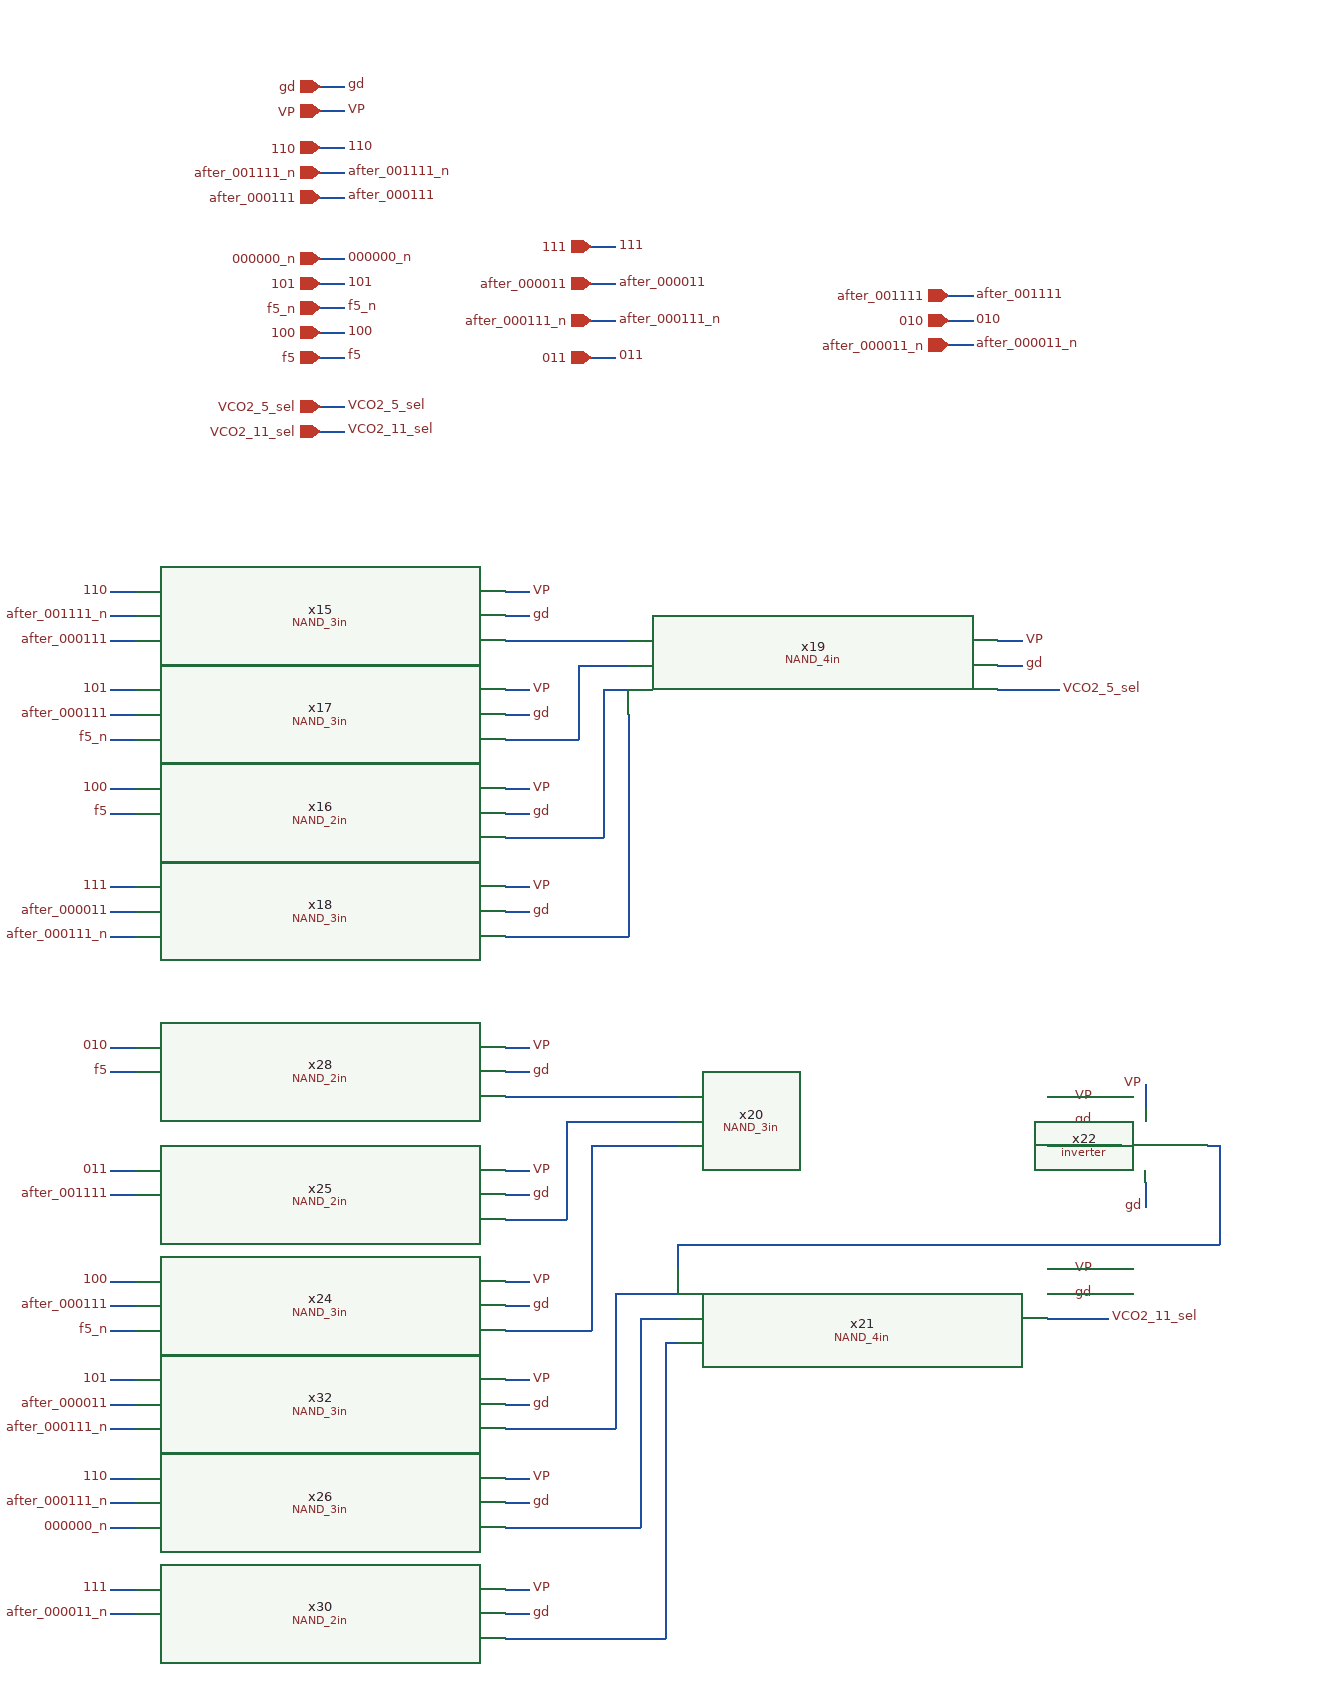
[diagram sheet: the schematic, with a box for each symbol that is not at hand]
v {xschem version=3.4.8RC file_version=1.3}
G {}
K {}
V {}
S {}
F {}
E {}
N 2000 -3300 2020 -3300 {lab=gd}
N 2000 -3280 2020 -3280 {lab=VP}
N 2000 -3230 2020 -3230 {lab=after_001111_n}
N 2000 -3210 2020 -3210 {lab=after_000111}
N 2000 -3160 2020 -3160 {lab=000000_n}
N 2000 -3250 2020 -3250 {lab=110}
N 2000 -3020 2020 -3020 {lab=VCO2_11_sel}
N 2000 -3040 2020 -3040 {lab=VCO2_5_sel}
N 2000 -3140 2020 -3140 {lab=101}
N 2000 -3120 2020 -3120 {lab=f5_n}
N 2000 -3100 2020 -3100 {lab=100}
N 2000 -3080 2020 -3080 {lab=f5}
N 2220 -3080 2240 -3080 {lab=011}
N 2220 -3110 2240 -3110 {lab=after_000111_n}
N 2220 -3140 2240 -3140 {lab=after_000011}
N 2220 -3170 2240 -3170 {lab=111}
N 2510 -3090 2530 -3090 {lab=after_000011_n}
N 2510 -3110 2530 -3110 {lab=010}
N 2510 -3130 2530 -3130 {lab=after_001111}
N 2150 -2870 2170 -2870 {lab=gd}
N 2150 -2890 2170 -2890 {lab=VP}
N 2150 -2710 2170 -2710 {lab=gd}
N 2150 -2730 2170 -2730 {lab=VP}
N 2150 -2790 2170 -2790 {lab=gd}
N 2150 -2810 2170 -2810 {lab=VP}
N 2150 -2630 2170 -2630 {lab=gd}
N 2150 -2650 2170 -2650 {lab=VP}
N 1830 -2890 1850 -2890 {lab=110}
N 1830 -2870 1850 -2870 {lab=after_001111_n}
N 1830 -2850 1850 -2850 {lab=after_000111}
N 1830 -2810 1850 -2810 {lab=101}
N 1830 -2790 1850 -2790 {lab=after_000111}
N 1830 -2770 1850 -2770 {lab=f5_n}
N 1830 -2650 1850 -2650 {lab=111}
N 1830 -2610 1850 -2610 {lab=after_000111_n}
N 1830 -2730 1850 -2730 {lab=100}
N 1830 -2710 1850 -2710 {lab=f5}
N 2150 -2850 2250 -2850 {lab=#net1}
N 2150 -2770 2210 -2770 {lab=#net2}
N 2210 -2830 2210 -2770 {lab=#net2}
N 2210 -2830 2250 -2830 {lab=#net2}
N 2230 -2810 2250 -2810 {lab=#net3}
N 2230 -2810 2230 -2690 {lab=#net3}
N 2150 -2690 2230 -2690 {lab=#net3}
N 2150 -2610 2250 -2610 {lab=#net4}
N 2250 -2790 2250 -2610 {lab=#net4}
N 2550 -2830 2570 -2830 {lab=gd}
N 2550 -2850 2570 -2850 {lab=VP}
N 2550 -2810 2600 -2810 {lab=VCO2_5_sel}
N 2590 -2460 2610 -2460 {lab=gd}
N 2590 -2480 2610 -2480 {lab=VP}
N 2150 -2310 2170 -2310 {lab=gd}
N 2150 -2330 2170 -2330 {lab=VP}
N 2150 -2400 2170 -2400 {lab=gd}
N 2150 -2420 2170 -2420 {lab=VP}
N 2150 -2290 2220 -2290 {lab=#net5}
N 2150 -2380 2200 -2380 {lab=#net6}
N 2150 -2500 2170 -2500 {lab=gd}
N 2150 -2520 2170 -2520 {lab=VP}
N 2150 -2060 2170 -2060 {lab=gd}
N 2150 -2080 2170 -2080 {lab=VP}
N 2150 -2040 2280 -2040 {lab=#net7}
N 2150 -2230 2170 -2230 {lab=gd}
N 2150 -2250 2170 -2250 {lab=VP}
N 2150 -2210 2240 -2210 {lab=#net8}
N 1830 -2630 1850 -2630 {lab=after_000011}
N 1830 -2330 1850 -2330 {lab=100}
N 1830 -2290 1850 -2290 {lab=f5_n}
N 1830 -2310 1850 -2310 {lab=after_000111}
N 1830 -2250 1850 -2250 {lab=101}
N 1830 -2210 1850 -2210 {lab=after_000111_n}
N 1830 -2230 1850 -2230 {lab=after_000011}
N 1830 -2520 1850 -2520 {lab=010}
N 1830 -2500 1850 -2500 {lab=f5}
N 1830 -2420 1850 -2420 {lab=011}
N 1830 -2400 1850 -2400 {lab=after_001111}
N 1830 -2080 1850 -2080 {lab=111}
N 1830 -2060 1850 -2060 {lab=after_000011_n}
N 2590 -2440 2650 -2440 {lab=#net9}
N 2150 -2150 2170 -2150 {lab=gd}
N 2150 -2170 2170 -2170 {lab=VP}
N 1830 -2170 1850 -2170 {lab=110}
N 1830 -2150 1850 -2150 {lab=after_000111_n}
N 1830 -2130 1850 -2130 {lab=000000_n}
N 2590 -2320 2610 -2320 {lab=gd}
N 2590 -2340 2610 -2340 {lab=VP}
N 2590 -2300 2640 -2300 {lab=VCO2_11_sel}
N 2670 -2410 2670 -2390 {lab=gd}
N 2670 -2490 2670 -2470 {lab=VP}
N 2720 -2440 2730 -2440 {lab=#net10}
N 2730 -2440 2730 -2360 {lab=#net10}
N 2290 -2360 2730 -2360 {lab=#net10}
N 2290 -2360 2290 -2340 {lab=#net10}
N 2150 -2480 2290 -2480 {lab=#net11}
N 2200 -2460 2200 -2380 {lab=#net6}
N 2200 -2460 2290 -2460 {lab=#net6}
N 2220 -2440 2290 -2440 {lab=#net5}
N 2220 -2440 2220 -2290 {lab=#net5}
N 2240 -2320 2240 -2210 {lab=#net8}
N 2240 -2320 2290 -2320 {lab=#net8}
N 2260 -2300 2290 -2300 {lab=#net12}
N 2260 -2300 2260 -2130 {lab=#net12}
N 2150 -2130 2260 -2130 {lab=#net12}
N 2280 -2280 2280 -2040 {lab=#net7}
N 2280 -2280 2290 -2280 {lab=#net7}
C {iopin.sym} 2000 -3300 2 0 {name=p46 lab=gd}
C {lab_wire.sym} 2020 -3300 2 0 {name=p53 sig_type=std_logic lab=gd}
C {iopin.sym} 2000 -3280 2 0 {name=p54 lab=VP}
C {ipin.sym} 2000 -3230 0 0 {name=p2 lab=after_001111_n}
C {lab_wire.sym} 2020 -3230 2 0 {name=p56 sig_type=std_logic lab=after_001111_n}
C {ipin.sym} 2000 -3210 0 0 {name=p57 lab=after_000111}
C {lab_wire.sym} 2020 -3210 2 0 {name=p58 sig_type=std_logic lab=after_000111}
C {ipin.sym} 2000 -3160 0 0 {name=p61 lab=000000_n}
C {lab_wire.sym} 2020 -3160 2 0 {name=p63 sig_type=std_logic lab=000000_n}
C {ipin.sym} 2000 -3250 0 0 {name=p20 lab=110}
C {lab_wire.sym} 2020 -3250 2 0 {name=p21 sig_type=std_logic lab=110}
C {lab_wire.sym} 2020 -3280 2 0 {name=p1 sig_type=std_logic lab=VP}
C {opin.sym} 2000 -3020 0 1 {name=p6 lab=VCO2_11_sel}
C {lab_wire.sym} 2020 -3020 2 0 {name=p7 sig_type=std_logic lab=VCO2_11_sel}
C {opin.sym} 2000 -3040 0 1 {name=p14 lab=VCO2_5_sel}
C {lab_wire.sym} 2020 -3040 2 0 {name=p15 sig_type=std_logic lab=VCO2_5_sel}
C {ipin.sym} 2000 -3140 0 0 {name=p19 lab=101}
C {lab_wire.sym} 2020 -3140 2 0 {name=p22 sig_type=std_logic lab=101}
C {ipin.sym} 2000 -3120 0 0 {name=p23 lab=f5_n}
C {lab_wire.sym} 2020 -3120 2 0 {name=p24 sig_type=std_logic lab=f5_n}
C {ipin.sym} 2000 -3100 0 0 {name=p25 lab=100}
C {lab_wire.sym} 2020 -3100 2 0 {name=p26 sig_type=std_logic lab=100}
C {ipin.sym} 2000 -3080 0 0 {name=p27 lab=f5}
C {lab_wire.sym} 2020 -3080 2 0 {name=p28 sig_type=std_logic lab=f5}
C {ipin.sym} 2220 -3080 0 0 {name=p3 lab=011}
C {lab_wire.sym} 2240 -3080 2 0 {name=p4 sig_type=std_logic lab=011}
C {ipin.sym} 2220 -3110 0 0 {name=p5 lab=after_000111_n}
C {lab_wire.sym} 2240 -3110 2 0 {name=p8 sig_type=std_logic lab=after_000111_n}
C {ipin.sym} 2220 -3140 0 0 {name=p9 lab=after_000011}
C {lab_wire.sym} 2240 -3140 2 0 {name=p10 sig_type=std_logic lab=after_000011}
C {ipin.sym} 2220 -3170 0 0 {name=p11 lab=111}
C {lab_wire.sym} 2240 -3170 2 0 {name=p12 sig_type=std_logic lab=111}
C {ipin.sym} 2510 -3090 0 0 {name=p17 lab=after_000011_n}
C {lab_wire.sym} 2530 -3090 2 0 {name=p18 sig_type=std_logic lab=after_000011_n}
C {ipin.sym} 2510 -3110 0 0 {name=p29 lab=010}
C {lab_wire.sym} 2530 -3110 2 0 {name=p30 sig_type=std_logic lab=010}
C {ipin.sym} 2510 -3130 0 0 {name=p31 lab=after_001111}
C {lab_wire.sym} 2530 -3130 2 0 {name=p32 sig_type=std_logic lab=after_001111}
C {lab_wire.sym} 1830 -2810 0 0 {name=p124 sig_type=std_logic lab=101}
C {lab_wire.sym} 1830 -2890 0 0 {name=p125 sig_type=std_logic lab=110}
C {NAND_3in.sym} 2000 -2870 0 0 {name=x15}
C {NAND_2in.sym} 2000 -2710 0 0 {name=x16}
C {lab_wire.sym} 2170 -2890 2 0 {name=p130 sig_type=std_logic lab=VP}
C {lab_wire.sym} 2170 -2870 2 0 {name=p131 sig_type=std_logic lab=gd}
C {lab_wire.sym} 2170 -2730 2 0 {name=p132 sig_type=std_logic lab=VP}
C {lab_wire.sym} 2170 -2710 2 0 {name=p133 sig_type=std_logic lab=gd}
C {NAND_3in.sym} 2000 -2790 0 0 {name=x17}
C {lab_wire.sym} 2170 -2810 2 0 {name=p134 sig_type=std_logic lab=VP}
C {lab_wire.sym} 2170 -2790 2 0 {name=p135 sig_type=std_logic lab=gd}
C {NAND_3in.sym} 2000 -2630 0 0 {name=x18}
C {lab_wire.sym} 2170 -2650 2 0 {name=p136 sig_type=std_logic lab=VP}
C {lab_wire.sym} 2170 -2630 2 0 {name=p137 sig_type=std_logic lab=gd}
C {lab_wire.sym} 1830 -2730 0 0 {name=p140 sig_type=std_logic lab=100}
C {lab_wire.sym} 1830 -2650 0 0 {name=p141 sig_type=std_logic lab=111}
C {lab_wire.sym} 1830 -2870 0 0 {name=p142 sig_type=std_logic lab=after_001111_n}
C {lab_wire.sym} 1830 -2850 0 0 {name=p145 sig_type=std_logic lab=after_000111}
C {lab_wire.sym} 1830 -2790 0 0 {name=p146 sig_type=std_logic lab=after_000111}
C {lab_wire.sym} 1830 -2770 0 0 {name=p147 sig_type=std_logic lab=f5_n}
C {lab_wire.sym} 1830 -2710 0 0 {name=p90 sig_type=std_logic lab=f5}
C {lab_wire.sym} 1830 -2630 0 0 {name=p91 sig_type=std_logic lab=after_000011}
C {lab_wire.sym} 1830 -2610 0 0 {name=p94 sig_type=std_logic lab=after_000111_n}
C {NAND_4in.sym} 2400 -2820 0 0 {name=x19}
C {lab_wire.sym} 2570 -2850 2 0 {name=p148 sig_type=std_logic lab=VP}
C {lab_wire.sym} 2570 -2830 2 0 {name=p149 sig_type=std_logic lab=gd}
C {lab_wire.sym} 2600 -2810 2 0 {name=p150 sig_type=std_logic lab=VCO2_5_sel}
C {NAND_3in.sym} 2440 -2460 0 0 {name=x20}
C {lab_wire.sym} 2610 -2480 2 0 {name=p157 sig_type=std_logic lab=VP}
C {lab_wire.sym} 2610 -2460 2 0 {name=p158 sig_type=std_logic lab=gd}
C {NAND_3in.sym} 2000 -2310 0 0 {name=x24}
C {lab_wire.sym} 2170 -2330 2 0 {name=p159 sig_type=std_logic lab=VP}
C {lab_wire.sym} 2170 -2310 2 0 {name=p160 sig_type=std_logic lab=gd}
C {NAND_2in.sym} 2000 -2400 0 0 {name=x25}
C {lab_wire.sym} 2170 -2420 2 0 {name=p161 sig_type=std_logic lab=VP}
C {lab_wire.sym} 2170 -2400 2 0 {name=p162 sig_type=std_logic lab=gd}
C {NAND_2in.sym} 2000 -2500 0 0 {name=x28}
C {lab_wire.sym} 2170 -2520 2 0 {name=p167 sig_type=std_logic lab=VP}
C {lab_wire.sym} 2170 -2500 2 0 {name=p168 sig_type=std_logic lab=gd}
C {NAND_2in.sym} 2000 -2060 0 0 {name=x30}
C {lab_wire.sym} 2170 -2080 2 0 {name=p171 sig_type=std_logic lab=VP}
C {lab_wire.sym} 2170 -2060 2 0 {name=p172 sig_type=std_logic lab=gd}
C {NAND_3in.sym} 2000 -2230 0 0 {name=x32}
C {lab_wire.sym} 2170 -2250 2 0 {name=p175 sig_type=std_logic lab=VP}
C {lab_wire.sym} 2170 -2230 2 0 {name=p176 sig_type=std_logic lab=gd}
C {lab_wire.sym} 1830 -2330 0 0 {name=p193 sig_type=std_logic lab=100}
C {lab_wire.sym} 1830 -2420 0 0 {name=p194 sig_type=std_logic lab=011}
C {lab_wire.sym} 1830 -2520 0 0 {name=p195 sig_type=std_logic lab=010}
C {lab_wire.sym} 1830 -2080 0 0 {name=p196 sig_type=std_logic lab=111}
C {lab_wire.sym} 1830 -2250 0 0 {name=p197 sig_type=std_logic lab=101}
C {lab_wire.sym} 1830 -2310 0 0 {name=p198 sig_type=std_logic lab=after_000111}
C {lab_wire.sym} 1830 -2290 0 0 {name=p201 sig_type=std_logic lab=f5_n}
C {lab_wire.sym} 1830 -2400 0 0 {name=p202 sig_type=std_logic lab=after_001111}
C {lab_wire.sym} 1830 -2500 0 0 {name=p203 sig_type=std_logic lab=f5}
C {lab_wire.sym} 1830 -2060 0 0 {name=p204 sig_type=std_logic lab=after_000011_n}
C {lab_wire.sym} 1830 -2230 0 0 {name=p205 sig_type=std_logic lab=after_000011}
C {lab_wire.sym} 1830 -2210 0 0 {name=p206 sig_type=std_logic lab=after_000111_n}
C {NAND_3in.sym} 2000 -2150 0 0 {name=x26}
C {lab_wire.sym} 2170 -2170 2 0 {name=p92 sig_type=std_logic lab=VP}
C {lab_wire.sym} 2170 -2150 2 0 {name=p93 sig_type=std_logic lab=gd}
C {lab_wire.sym} 1830 -2170 0 0 {name=p95 sig_type=std_logic lab=110}
C {lab_wire.sym} 1830 -2150 0 0 {name=p96 sig_type=std_logic lab=after_000111_n}
C {lab_wire.sym} 1830 -2130 0 0 {name=p138 sig_type=std_logic lab=000000_n}
C {NAND_4in.sym} 2440 -2310 0 0 {name=x21}
C {lab_wire.sym} 2610 -2340 2 0 {name=p139 sig_type=std_logic lab=VP}
C {lab_wire.sym} 2610 -2320 2 0 {name=p143 sig_type=std_logic lab=gd}
C {lab_wire.sym} 2640 -2300 2 0 {name=p144 sig_type=std_logic lab=VCO2_11_sel}
C {inverter.sym} 2670 -2440 0 0 {name=x22}
C {lab_wire.sym} 2670 -2390 3 0 {name=p151 sig_type=std_logic lab=gd}
C {lab_wire.sym} 2670 -2490 1 0 {name=p152 sig_type=std_logic lab=VP}
